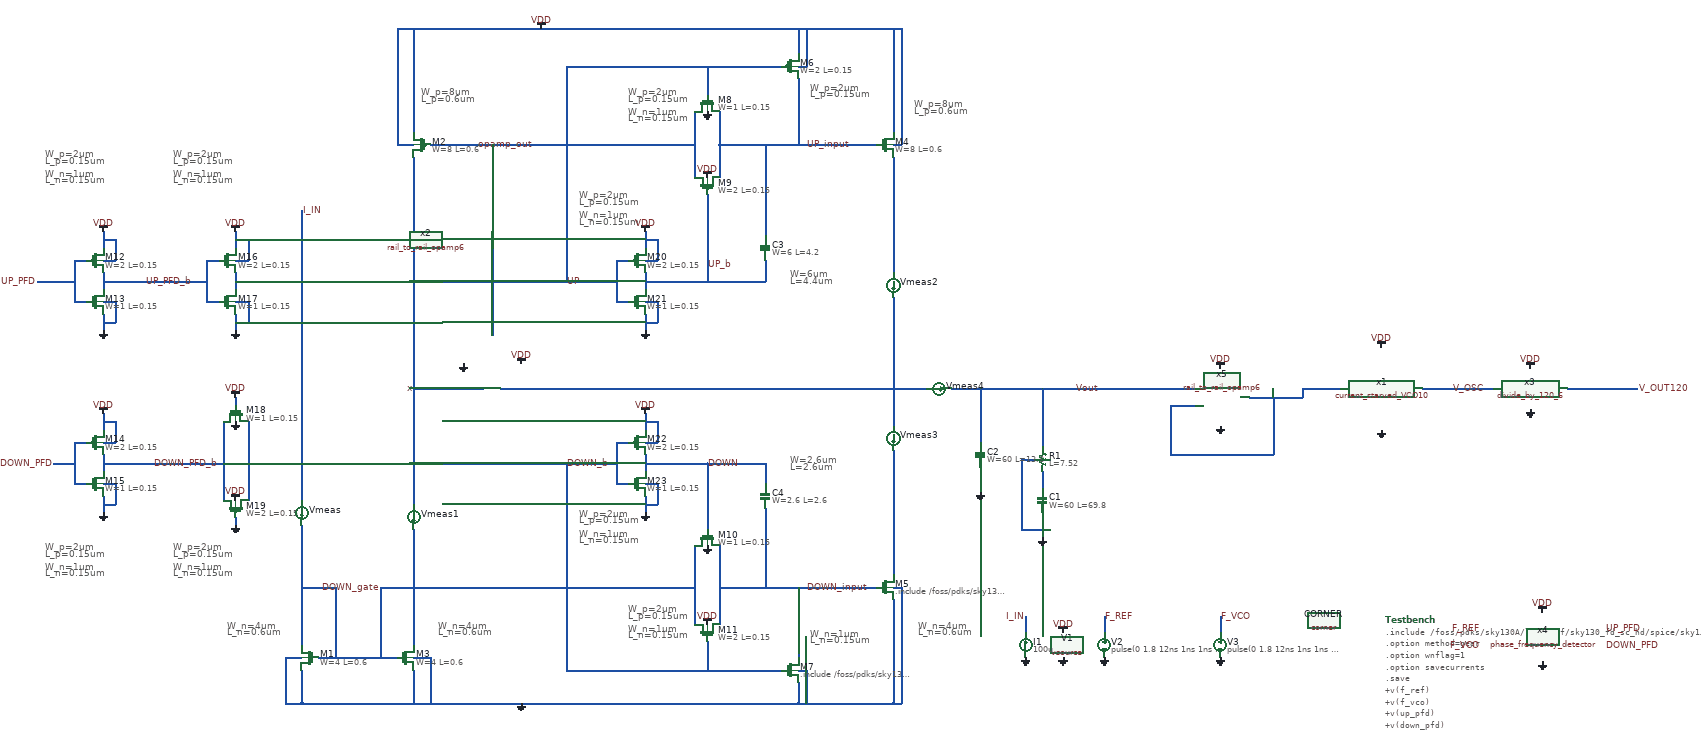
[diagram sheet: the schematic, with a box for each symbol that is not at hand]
v {xschem version=3.4.6 file_version=1.2}
G {}
K {}
V {}
S {}
E {}
B 2 2860 -2340 4220 -1670 {flags=graph
y1=0.88424229
y2=0.88833829
ypos1=0
ypos2=2
divy=5
subdivy=1
unity=1
x1=1.1050946e-07
x2=1.1771522e-07
divx=5
subdivx=1
xlabmag=1.0
ylabmag=1.0


dataset=0
unitx=1
logx=0
logy=0








linewidth_mult=1





color=6
node=vout}
B 2 2860 -3040 4220 -2370 {flags=graph
y1=-0.036
y2=1.7
ypos1=0
ypos2=2
divy=5
subdivy=1
unity=1
x1=1.1050946e-07
x2=1.1771522e-07
divx=5
subdivx=1
xlabmag=1.0
ylabmag=1.0


dataset=0
unitx=1
logx=0
logy=0








linewidth_mult=1




color=7
node=v_osc}
T {W_p=2um
L_p=0.15um

W_n=1um
L_n=0.15um} 550 -2010 0 0 0.4 0.4 {}
T {W_p=2um
L_p=0.15um

W_n=1um
L_n=0.15um} 550 -1060 0 0 0.4 0.4 {}
T {W_p=2um
L_p=0.15um

W_n=1um
L_n=0.15um} 860 -2010 0 0 0.4 0.4 {}
T {W_p=2um
L_p=0.15um

W_n=1um
L_n=0.15um} 860 -1060 0 0 0.4 0.4 {}
T {W_p=2um
L_p=0.15um

W_n=1um
L_n=0.15um} 1840 -1910 0 0 0.4 0.4 {}
T {W_p=2um
L_p=0.15um

W_n=1um
L_n=0.15um} 1840 -1140 0 0 0.4 0.4 {}
T {W_n=4um
L_n=0.6um} 990 -870 0 0 0.4 0.4 {}
T {W_n=4um
L_n=0.6um} 1500 -870 0 0 0.4 0.4 {}
T {W_p=2um
L_p=0.15um

W_n=1um
L_n=0.15um} 1960 -910 0 0 0.4 0.4 {}
T {W_p=2um
L_p=0.15um

W_n=1um
L_n=0.15um} 1960 -2160 0 0 0.4 0.4 {}
T {W_p=8um
L_p=0.6um} 1460 -2160 0 0 0.4 0.4 {}
T {W_p=8um
L_p=0.6um} 2650 -2130 0 0 0.4 0.4 {}
T {W_n=4um
L_n=0.6um} 2660 -870 0 0 0.4 0.4 {}
T {W_n=1um
L_n=0.15um} 2400 -850 0 0 0.4 0.4 {}
T {W_p=2um
L_p=0.15um} 2400 -2170 0 0 0.4 0.4 {}
T {W=2.6um
L=2.6um} 2350 -1270 0 0 0.4 0.4 {}
T {W=6um
L=4.4um} 2350 -1720 0 0 0.4 0.4 {}
N 2960 -1230 2960 -1180 {
lab=#net1}
N 2960 -1430 2960 -1290 {
lab=Vout}
N 2960 -1130 2960 -1070 {
lab=GND}
N 2910 -1260 2940 -1260 {
lab=GND}
N 2910 -1260 2910 -1090 {
lab=GND}
N 2910 -1090 2960 -1090 {
lab=GND}
N 2810 -1430 2810 -1290 {
lab=Vout}
N 2810 -1240 2810 -1180 {
lab=GND}
N 3110 -880 3110 -840 {
lab=F_REF}
N 3390 -880 3390 -840 {
lab=F_VCO}
N 2740 -1430 3040 -1430 {
lab=Vout}
N 2920 -880 2920 -840 {
lab=I_IN}
N 1210 -780 1400 -780 {
lab=DOWN_gate}
N 1170 -750 1170 -670 {
lab=GND}
N 1170 -670 1730 -670 {
lab=GND}
N 1130 -780 1170 -780 {
lab=GND}
N 1130 -780 1130 -670 {
lab=GND}
N 1130 -670 1170 -670 {
lab=GND}
N 1440 -780 1480 -780 {
lab=GND}
N 1400 -2020 1440 -2020 {
lab=VDD}
N 1730 -670 1770 -670 {
lab=GND}
N 1440 -2300 1440 -2050 {
lab=VDD}
N 1400 -2300 1400 -2020 {
lab=VDD}
N 2600 -2300 2600 -2050 {
lab=VDD}
N 2370 -2300 2370 -2240 {
lab=VDD}
N 2370 -2210 2390 -2210 {
lab=VDD}
N 2390 -2300 2390 -2210 {
lab=VDD}
N 2620 -2300 2620 -2020 {
lab=VDD}
N 2600 -2020 2620 -2020 {
lab=VDD}
N 2600 -1990 2600 -1710 {
lab=#net2}
N 1770 -670 2370 -670 {
lab=GND}
N 2370 -720 2370 -670 {
lab=GND}
N 2600 -950 2620 -950 {
lab=GND}
N 2600 -670 2620 -670 {
lab=GND}
N 790 -1690 890 -1690 {
lab=UP_PFD_b}
N 830 -1250 980 -1250 {
lab=DOWN_PFD_b}
N 530 -1690 570 -1690 {
lab=UP_PFD}
N 570 -1250 610 -1250 {
lab=DOWN_PFD}
N 1440 -1990 1440 -1550 {
lab=x}
N 1440 -1430 1610 -1430 {
lab=x}
N 1650 -1430 2600 -1430 {
lab=#net3}
N 1630 -2020 1630 -1560 {
lab=opamp_out}
N 1250 -950 1250 -780 {
lab=DOWN_gate}
N 1170 -950 1250 -950 {
lab=DOWN_gate}
N 1480 -780 1480 -670 {
lab=GND}
N 1440 -750 1440 -670 {
lab=GND}
N 1360 -950 2120 -950 {
lab=DOWN_gate}
N 1040 -1250 1880 -1250 {
lab=DOWN_b}
N 2150 -1900 2150 -1690 {
lab=UP_b}
N 1810 -2210 2330 -2210 {
lab=UP}
N 1810 -2210 1810 -1690 {
lab=UP}
N 2370 -2180 2370 -2020 {
lab=UP_input}
N 2180 -2020 2560 -2020 {
lab=UP_input}
N 1400 -2300 2620 -2300 {
lab=VDD}
N 2090 -1250 2150 -1250 {
lab=DOWN}
N 2150 -1250 2150 -1090 {
lab=DOWN}
N 1810 -1250 1810 -750 {
lab=DOWN_b}
N 1810 -750 2330 -750 {
lab=DOWN_b}
N 980 -1350 980 -1160 {
lab=DOWN_PFD_b}
N 1040 -1350 1040 -1160 {
lab=DOWN_b}
N 1010 -1410 1010 -1390 {
lab=VDD}
N 1010 -1120 1010 -1100 {
lab=GND}
N 690 -1270 690 -1230 {
lab=DOWN_PFD_b}
N 620 -1300 650 -1300 {
lab=DOWN_PFD}
N 620 -1300 620 -1200 {
lab=DOWN_PFD}
N 620 -1200 650 -1200 {
lab=DOWN_PFD}
N 690 -1250 830 -1250 {
lab=DOWN_PFD_b}
N 610 -1250 620 -1250 {
lab=DOWN_PFD}
N 690 -1170 690 -1130 {
lab=GND}
N 690 -1370 690 -1330 {
lab=VDD}
N 690 -1300 720 -1300 {
lab=VDD}
N 720 -1350 720 -1300 {
lab=VDD}
N 690 -1350 720 -1350 {
lab=VDD}
N 690 -1200 720 -1200 {
lab=GND}
N 720 -1200 720 -1150 {
lab=GND}
N 690 -1150 720 -1150 {
lab=GND}
N 690 -1710 690 -1670 {
lab=UP_PFD_b}
N 620 -1740 650 -1740 {
lab=UP_PFD}
N 620 -1740 620 -1640 {
lab=UP_PFD}
N 620 -1640 650 -1640 {
lab=UP_PFD}
N 690 -1690 790 -1690 {
lab=UP_PFD_b}
N 570 -1690 620 -1690 {
lab=UP_PFD}
N 690 -1610 690 -1570 {
lab=GND}
N 690 -1810 690 -1770 {
lab=VDD}
N 690 -1740 720 -1740 {
lab=VDD}
N 720 -1790 720 -1740 {
lab=VDD}
N 690 -1790 720 -1790 {
lab=VDD}
N 690 -1640 720 -1640 {
lab=GND}
N 720 -1640 720 -1590 {
lab=GND}
N 690 -1590 720 -1590 {
lab=GND}
N 1010 -1710 1010 -1670 {
lab=UP}
N 940 -1740 970 -1740 {
lab=UP_PFD_b}
N 940 -1740 940 -1640 {
lab=UP_PFD_b}
N 940 -1640 970 -1640 {
lab=UP_PFD_b}
N 890 -1690 940 -1690 {
lab=UP_PFD_b}
N 1010 -1610 1010 -1570 {
lab=GND}
N 1010 -1810 1010 -1770 {
lab=VDD}
N 1010 -1740 1040 -1740 {
lab=VDD}
N 1040 -1790 1040 -1740 {
lab=VDD}
N 1010 -1790 1040 -1790 {
lab=VDD}
N 1010 -1640 1040 -1640 {
lab=GND}
N 1040 -1640 1040 -1590 {
lab=GND}
N 1010 -1590 1040 -1590 {
lab=GND}
N 2000 -1270 2000 -1230 {
lab=DOWN}
N 1930 -1300 1960 -1300 {
lab=DOWN_b}
N 1930 -1300 1930 -1200 {
lab=DOWN_b}
N 1930 -1200 1960 -1200 {
lab=DOWN_b}
N 1880 -1250 1930 -1250 {
lab=DOWN_b}
N 2000 -1170 2000 -1130 {
lab=GND}
N 2000 -1370 2000 -1330 {
lab=VDD}
N 2000 -1300 2030 -1300 {
lab=VDD}
N 2030 -1350 2030 -1300 {
lab=VDD}
N 2000 -1350 2030 -1350 {
lab=VDD}
N 2000 -1200 2030 -1200 {
lab=GND}
N 2030 -1200 2030 -1150 {
lab=GND}
N 2000 -1150 2030 -1150 {
lab=GND}
N 2000 -1250 2090 -1250 {
lab=DOWN}
N 2000 -1710 2000 -1670 {
lab=UP_b}
N 1930 -1740 1960 -1740 {
lab=UP}
N 1930 -1740 1930 -1640 {
lab=UP}
N 1930 -1640 1960 -1640 {
lab=UP}
N 1810 -1690 1930 -1690 {
lab=UP}
N 2000 -1610 2000 -1570 {
lab=GND}
N 2000 -1810 2000 -1770 {
lab=VDD}
N 2000 -1740 2030 -1740 {
lab=VDD}
N 2030 -1790 2030 -1740 {
lab=VDD}
N 2000 -1790 2030 -1790 {
lab=VDD}
N 2000 -1640 2030 -1640 {
lab=GND}
N 2030 -1640 2030 -1590 {
lab=GND}
N 2000 -1590 2030 -1590 {
lab=GND}
N 2000 -1690 2090 -1690 {
lab=UP_b}
N 2090 -1690 2150 -1690 {
lab=UP_b}
N 1010 -1690 1810 -1690 {
lab=UP}
N 1440 -1550 1440 -1490 {
lab=x}
N 1170 -1860 1170 -1160 {
lab=I_IN}
N 1440 -1490 1440 -1150 {
lab=x}
N 1440 -1070 1440 -810 {
lab=#net4}
N 1170 -1100 1170 -1090 {
lab=DOWN_gate}
N 1170 -990 1170 -810 {
lab=DOWN_gate}
N 1440 -1090 1440 -1070 {
lab=#net4}
N 1170 -1090 1170 -990 {
lab=DOWN_gate}
N 2180 -2100 2180 -2020 {
lab=UP_input}
N 2120 -2100 2120 -1940 {
lab=opamp_out}
N 2180 -2020 2180 -1940 {
lab=UP_input}
N 1480 -2020 2120 -2020 {
lab=opamp_out}
N 2370 -670 2600 -670 {
lab=GND}
N 2180 -1050 2180 -860 {
lab=DOWN_input}
N 2120 -1050 2120 -860 {
lab=DOWN_gate}
N 2180 -950 2560 -950 {
lab=DOWN_input}
N 2600 -920 2600 -670 {
lab=GND}
N 2620 -950 2620 -670 {
lab=GND}
N 1360 -950 1360 -780 {
lab=DOWN_gate}
N 2370 -950 2370 -780 {
lab=DOWN_input}
N 2370 -750 2390 -750 {
lab=GND}
N 2390 -750 2390 -670 {
lab=GND}
N 2150 -2210 2150 -2140 {
lab=UP}
N 2600 -1280 2600 -980 {
lab=#net5}
N 2600 -1430 2600 -1340 {
lab=#net3}
N 2600 -1650 2600 -1430 {
lab=#net3}
N 2150 -1690 2290 -1690 {
lab=UP_b}
N 2290 -1740 2290 -1690 {
lab=UP_b}
N 2290 -2020 2290 -1800 {
lab=UP_input}
N 2290 -1250 2290 -1200 {
lab=DOWN}
N 2290 -1140 2290 -950 {
lab=DOWN_input}
N 2150 -1250 2290 -1250 {
lab=DOWN}
N 2600 -1430 2680 -1430 {
lab=#net3}
N 2150 -820 2150 -750 {
lab=DOWN_b}
N 3880 -1430 4050 -1430 {lab=V_OSC}
N 4230 -1430 4400 -1430 {lab=V_OUT120}
N 3040 -1430 3260 -1430 {lab=Vout}
N 3260 -1430 3330 -1430 {lab=Vout}
N 3460 -1410 3590 -1410 {lab=#net6}
N 3590 -1430 3590 -1410 {lab=#net6}
N 3590 -1430 3680 -1430 {lab=#net6}
N 3520 -1410 3520 -1270 {lab=#net6}
N 3270 -1270 3520 -1270 {lab=#net6}
N 3270 -1390 3270 -1270 {lab=#net6}
N 3270 -1390 3330 -1390 {lab=#net6}
C {sky130_fd_pr/corner.sym} 3640 -870 0 0 {name=CORNER only_toplevel=false corner=tt
value="

.include /foss/pdks/sky130A/libs.ref/sky130_fd_sc_hd/spice/sky130_fd_sc_hd.spice

.option method=gear
.option wnflag=1

* V_out initial voltage value for the F_VCO delay of 2ns  (leading)
* .ic v(vout) = 1.8

* V_out initial voltage value for the F_VCO delay of 12ns (lock condition)
.ic v(vout) = 0.83

* V_out initial voltage value for the F_VCO delay of 22ns (lagging)
* .ic v(vout) = 0

.control
  save v(f_ref) save v(f_vco) save v(i_in) save v(up_pfd) v(down_pfd) v(up_pfd_b) v(down_pfd_b) v(up) v(up_b) v(down) v(down_b) v(x) v(opamp_out) v(up_input) v(down_input) v(down_gate) v(vout)

  * timestep for exact simulation results
  * tran 5ps 0.5us

  * timestep for faster simulation results
  tran 50ps 0.5us

  remzerovec
  write pfd_charge_pump_10.raw
  set appendwrite

.endc

"


v(vout)="0.0

.control
  save all

  * timestep for exact simulation results
  tran 5ps 0.5us

  * timestep for faster simulation results
  * tran 50ps 0.5us

  remzerovec
  write pfd_chargA}
C {devices/code.sym} 3790 -871.25 0 0 {name=Testbench only_toplevel=false value="

.include /foss/pdks/sky130A/libs.ref/sky130_fd_sc_hd/spice/sky130_fd_sc_hd.spice

.option method=gear
.option wnflag=1
.option savecurrents

.save
+v(f_ref)
+v(f_vco)
+v(up_pfd)
+v(down_pfd)
+v(x4.up_pfd_b)
+v(x4.up_b)
+v(x4.down_b)
+v(x4.up)
+v(x4.down)
+v(x4.up_input)
+v(x4.down_input)
+v(x4.down_gate)
+v(x4.x)
+v(x4.opamp_out)
+i(x4.vmeas2)
+i(x4.vmeas3)
+@m.x2.xm1.msky130_fd_pr__nfet_01v8[gm]
+@m.x2.xm2.msky130_fd_pr__nfet_01v8[gm]
+@m.x2.xm3.msky130_fd_pr__nfet_01v8[gm]
+@m.x2.xm4.msky130_fd_pr__pfet_01v8[gm]
+@m.x2.xm5.msky130_fd_pr__pfet_01v8[gm]
+@m.x2.xm6.msky130_fd_pr__pfet_01v8[gm]
+@m.x2.xm7.msky130_fd_pr__pfet_01v8[gm]
+@m.x2.xm8.msky130_fd_pr__pfet_01v8[gm]
+@m.x2.xm9.msky130_fd_pr__nfet_01v8[gm]
+@m.x2.xm10.msky130_fd_pr__nfet_01v8[gm]
+@m.x2.xm11.msky130_fd_pr__pfet_01v8[gm]
+@m.x2.xm12.msky130_fd_pr__nfet_01v8[gm]
+@m.x2.xm13.msky130_fd_pr__pfet_01v8[gm]
+@m.x2.xm15.msky130_fd_pr__nfet_01v8[gm]
+v(v_cont)
+v(v_osc)
+v(vout)
+v(v_out120)

* V_out initial voltage value for the F_VCO delay of 2ns  (leading)
* .ic v(vout) = 1.8

* V_out initial voltage value for the F_VCO delay of 12ns (lock condition)
.ic v(vout) = 0.887

* V_out initial voltage value for the F_VCO delay of 22ns (lagging)
* .ic v(vout) = 0.0

.control
  * save v(f_ref) save v(f_vco) save v(i_in) save v(up_pfd) v(down_pfd) v(up_pfd_b) v(down_pfd_b) v(up) v(up_b) v(down) v(down_b) v(x) v(opamp_out) v(up_input) v(down_input) v(down_gate) v(vout)
  * save all

  * timestep for exact simulation results
  tran 5ps 0.5us

  * timestep for faster simulation results
  * tran 50ps 0.5us

  remzerovec
  write pfd_charge_pump_14.raw
  set appendwrite

.endc

"
}
C {devices/vsource.sym} 3010 -810 0 0 {name=V1 value=1.8 savecurrent=false}
C {devices/gnd.sym} 3010 -780 0 0 {name=l2 lab=GND}
C {devices/vdd.sym} 3010 -840 0 1 {name=l3 lab=VDD}
C {devices/lab_wire.sym} 3040 -1430 0 1 {name=p9 sig_type=std_logic lab=Vout}
C {sky130_fd_pr/cap_mim_m3_1.sym} 2810 -1270 0 0 {name=C2 model=cap_mim_m3_1 W=60 L=13.8 MF=1 spiceprefix=X}
C {sky130_fd_pr/cap_mim_m3_1.sym} 2960 -1160 0 0 {name=C1 model=cap_mim_m3_1 W=60 L=69.8 MF=1 spiceprefix=X}
C {devices/gnd.sym} 2960 -1070 0 0 {name=l4 lab=GND
value="

.include /foss/pdks/sky130A/libs.ref/sky130_fd_sc_hd/spice/sky130_fd_sc_hd.spice

.option method=gear
.option wnflag=1

* V_out initial voltage value for the F_VCO delay of 2ns  (leading)
* .ic v(vout) = 1.8

* V_out initial voltage value for the F_VCO delay of 12ns (lock condition)
.ic v(vout) = 0.83

* V_out initial voltage value for the F_VCO delay of 22ns (lagging)
* .ic v(vout) = 0

.control
  save v(f_ref) save v(f_vco) save v(i_in) save v(up_pfd) v(down_pfd) v(up_pfd_b) v(down_pfd_b) v(up) v(up_b) v(down) v(down_b) v(x) v(opamp_out) v(up_input) v(down_input) v(down_gate) v(vout)

  * timestep for exact simulation results
  * tran 5ps 0.5us

  * timestep for faster simulation results
  tran 50ps 0.5us

  remzerovec
  write pfd_charge_pump_10.raw
  set appendwrite

.endc

"}
C {devices/gnd.sym} 2810 -1180 0 0 {name=l9 lab=GND
W=60}
C {devices/vsource.sym} 3110 -810 0 0 {name=V2 value=pulse"(0 1.8 12ns 1ns 1ns 24ns 50ns)" savecurrent=false
* }
C {devices/gnd.sym} 3110 -780 0 0 {name=l10 lab=GND}
C {devices/lab_pin.sym} 3110 -880 0 1 {name=p11 sig_type=std_logic lab=F_REF}
C {devices/vsource.sym} 3390 -810 0 0 {name=V3 value="pulse(0 1.8 12ns 1ns 1ns 24ns 50ns)" savecurrent=false
* "sin(0.9 0.9 20.1MEG)" 1 AC 1}
C {devices/gnd.sym} 3390 -780 0 0 {name=l15 lab=GND}
C {devices/lab_pin.sym} 3390 -880 0 1 {name=p12 sig_type=std_logic lab=F_VCO}
C {/foss/designs/my_design/projects/pll/pfd/xschem_ngspice/phase_frequency_detector.sym} 4170 -830 0 0 {name=x4
value="

.include /foss/pdks/sky130A/libs.ref/sky130_fd_sc_hd/spice/sky130_fd_sc_hd.spice

.option method=gear
.option wnflag=1

* V_out initial voltage value for the F_VCO delay of 2ns  (leading)
* .ic v(vout) = 1.8

* V_out initial voltage value for the F_VCO delay of 12ns (lock condition)
.ic v(vout) = 0.83

* V_out initial voltage value for the F_VCO delay of 22ns (lagging)
* .ic v(vout) = 0

.control
  save v(f_ref) save v(f_vco) save v(i_in) save v(up_pfd) v(down_pfd) v(up_pfd_b) v(down_pfd_b) v(up) v(up_b) v(down) v(down_b) v(x) v(opamp_out) v(up_input) v(down_input) v(down_gate) v(vout)

  * timestep for exact simulation results
  * tran 5ps 0.5us

  * timestep for faster simulation results
  tran 50ps 0.5us

  remzerovec
  write pfd_charge_pump_10.raw
  set appendwrite

.endc

"


v(vout)="0.0

.control
  save all

  * timestep for exact simulation results
  tran 5ps 0.5us

  * timestep for faster simulation results
  * tran 50ps 0.5us

  remzerovec
  write pfd_charge_pump_10.raw
  set appendwrite

.!}
C {devices/lab_pin.sym} 4020 -850 0 0 {name=p19 lab=F_REF
value="

.include /foss/pdks/sky130A/libs.ref/sky130_fd_sc_hd/spice/sky130_fd_sc_hd.spice

.option method=gear
.option wnflag=1

* V_out initial voltage value for the F_VCO delay of 2ns  (leading)
* .ic v(vout) = 1.8

* V_out initial voltage value for the F_VCO delay of 12ns (lock condition)
.ic v(vout) = 0.83

* V_out initial voltage value for the F_VCO delay of 22ns (lagging)
* .ic v(vout) = 0

.control
  save v(f_ref) save v(f_vco) save v(i_in) save v(up_pfd) v(down_pfd) v(up_pfd_b) v(down_pfd_b) v(up) v(up_b) v(down) v(down_b) v(x) v(opamp_out) v(up_input) v(down_input) v(down_gate) v(vout)

  * timestep for exact simulation results
  * tran 5ps 0.5us

  * timestep for faster simulation results
  tran 50ps 0.5us

  remzerovec
  write pfd_charge_pump_10.raw
  set appendwrite

.endc

"


v(vout)="0.0

.control
  save all

  * timestep for exact simulation results
  tran 5ps 0.5us

  * timestep for faster simulation results
  * tran 50ps 0.5us

  remzerovec
  write pfd_charge_pump_10.raw
  set appA}
C {devices/lab_pin.sym} 4020 -810 0 0 {name=p20 lab=F_VCO
value="

.include /foss/pdks/sky130A/libs.ref/sky130_fd_sc_hd/spice/sky130_fd_sc_hd.spice

.option method=gear
.option wnflag=1

* V_out initial voltage value for the F_VCO delay of 2ns  (leading)
* .ic v(vout) = 1.8

* V_out initial voltage value for the F_VCO delay of 12ns (lock condition)
.ic v(vout) = 0.83

* V_out initial voltage value for the F_VCO delay of 22ns (lagging)
* .ic v(vout) = 0

.control
  save v(f_ref) save v(f_vco) save v(i_in) save v(up_pfd) v(down_pfd) v(up_pfd_b) v(down_pfd_b) v(up) v(up_b) v(down) v(down_b) v(x) v(opamp_out) v(up_input) v(down_input) v(down_gate) v(vout)

  * timestep for exact simulation results
  * tran 5ps 0.5us

  * timestep for faster simulation results
  tran 50ps 0.5us

  remzerovec
  write pfd_charge_pump_10.raw
  set appendwrite

.endc

"


v(vout)="0.0

.control
  save all

  * timestep for exact simulation results
  tran 5ps 0.5us

  * timestep for faster simulation results
  * tran 50ps 0.5us

  remzerovec
  write pfd_charge_pump_10.raw
  set appA}
C {devices/lab_wire.sym} 4320 -850 0 1 {name=p22 sig_type=std_logic lab=UP_PFD}
C {devices/lab_wire.sym} 4320 -810 2 0 {name=p23 sig_type=std_logic lab=DOWN_PFD}
C {devices/vdd.sym} 4170 -890 0 1 {name=l1 lab=VDD
value="

.include /foss/pdks/sky130A/libs.ref/sky130_fd_sc_hd/spice/sky130_fd_sc_hd.spice

.option method=gear
.option wnflag=1

* V_out initial voltage value for the F_VCO delay of 2ns  (leading)
* .ic v(vout) = 1.8

* V_out initial voltage value for the F_VCO delay of 12ns (lock condition)
.ic v(vout) = 0.83

* V_out initial voltage value for the F_VCO delay of 22ns (lagging)
* .ic v(vout) = 0

.control
  save v(f_ref) save v(f_vco) save v(i_in) save v(up_pfd) v(down_pfd) v(up_pfd_b) v(down_pfd_b) v(up) v(up_b) v(down) v(down_b) v(x) v(opamp_out) v(up_input) v(down_input) v(down_gate) v(vout)

  * timestep for exact simulation results
  * tran 5ps 0.5us

  * timestep for faster simulation results
  tran 50ps 0.5us

  remzerovec
  write pfd_charge_pump_10.raw
  set appendwrite

.endc

"


v(vout)="0.0

.control
  save all

  * timestep for exact simulation results
  tran 5ps 0.5us

  * timestep for faster simulation results
  * tran 50ps 0.5us

  remzerovec
  write pfd_charge_pump_10.raw
  set appendA}
C {devices/gnd.sym} 4170 -770 0 0 {name=l8 lab=GND
value="

.include /foss/pdks/sky130A/libs.ref/sky130_fd_sc_hd/spice/sky130_fd_sc_hd.spice

.option method=gear
.option wnflag=1

* V_out initial voltage value for the F_VCO delay of 2ns  (leading)
* .ic v(vout) = 1.8

* V_out initial voltage value for the F_VCO delay of 12ns (lock condition)
.ic v(vout) = 0.83

* V_out initial voltage value for the F_VCO delay of 22ns (lagging)
* .ic v(vout) = 0

.control
  save v(f_ref) save v(f_vco) save v(i_in) save v(up_pfd) v(down_pfd) v(up_pfd_b) v(down_pfd_b) v(up) v(up_b) v(down) v(down_b) v(x) v(opamp_out) v(up_input) v(down_input) v(down_gate) v(vout)

  * timestep for exact simulation results
  * tran 5ps 0.5us

  * timestep for faster simulation results
  tran 50ps 0.5us

  remzerovec
  write pfd_charge_pump_10.raw
  set appendwrite

.endc

"}
C {sky130_fd_pr/res_xhigh_po_0p35.sym} 2960 -1260 0 0 {name=R1
L=7.52
model=res_xhigh_po_0p35
spiceprefix=X
mult=1}
C {devices/isource.sym} 2920 -810 2 0 {name=I1 value=100u}
C {devices/gnd.sym} 2920 -780 0 0 {name=l26 lab=GND}
C {devices/lab_pin.sym} 2920 -880 2 1 {name=p3 sig_type=std_logic lab=I_IN}
C {devices/ammeter.sym} 2600 -1310 0 0 {name=Vmeas3 savecurrent=true spice_ignore=0}
C {sky130_fd_pr/nfet_01v8.sym} 1190 -780 0 1 {name=M1
L=0.6
W=4
nf=1 
mult=1
ad="'int((nf+1)/2) * W/nf * 0.29'" 
pd="'2*int((nf+1)/2) * (W/nf + 0.29)'"
as="'int((nf+2)/2) * W/nf * 0.29'" 
ps="'2*int((nf+2)/2) * (W/nf + 0.29)'"
nrd="'0.29 / W'" nrs="'0.29 / W'"
sa=0 sb=0 sd=0
model=nfet_01v8
spiceprefix=X
}
C {sky130_fd_pr/nfet_01v8.sym} 1420 -780 0 0 {name=M3
L=0.6
W=4
nf=1 
mult=1
ad="'int((nf+1)/2) * W/nf * 0.29'" 
pd="'2*int((nf+1)/2) * (W/nf + 0.29)'"
as="'int((nf+2)/2) * W/nf * 0.29'" 
ps="'2*int((nf+2)/2) * (W/nf + 0.29)'"
nrd="'0.29 / W'" nrs="'0.29 / W'"
sa=0 sb=0 sd=0
model=nfet_01v8
spiceprefix=X
}
C {sky130_fd_pr/pfet_01v8.sym} 1460 -2020 2 0 {name=M2
L=0.6
W=8
nf=8
mult=1
ad="'int((nf+1)/2) * W/nf * 0.29'" 
pd="'2*int((nf+1)/2) * (W/nf + 0.29)'"
as="'int((nf+2)/2) * W/nf * 0.29'" 
ps="'2*int((nf+2)/2) * (W/nf + 0.29)'"
nrd="'0.29 / W'" nrs="'0.29 / W'"
sa=0 sb=0 sd=0
model=pfet_01v8
spiceprefix=X
}
C {devices/vdd.sym} 1750 -2300 0 0 {name=l13 lab=VDD}
C {devices/gnd.sym} 1700 -670 0 0 {name=l14 lab=GND}
C {devices/lab_wire.sym} 1440 -1430 0 0 {name=p2 sig_type=std_logic lab=x}
C {sky130_fd_pr/pfet_01v8.sym} 2150 -1920 1 1 {name=M9
L=0.15
W=2
nf=2
mult=1
ad="'int((nf+1)/2) * W/nf * 0.29'" 
pd="'2*int((nf+1)/2) * (W/nf + 0.29)'"
as="'int((nf+2)/2) * W/nf * 0.29'" 
ps="'2*int((nf+2)/2) * (W/nf + 0.29)'"
nrd="'0.29 / W'" nrs="'0.29 / W'"
sa=0 sb=0 sd=0
model=pfet_01v8
spiceprefix=X
}
C {sky130_fd_pr/pfet_01v8.sym} 2350 -2210 0 0 {name=M6
L=0.15
W=2
nf=2
mult=1
ad="'int((nf+1)/2) * W/nf * 0.29'" 
pd="'2*int((nf+1)/2) * (W/nf + 0.29)'"
as="'int((nf+2)/2) * W/nf * 0.29'" 
ps="'2*int((nf+2)/2) * (W/nf + 0.29)'"
nrd="'0.29 / W'" nrs="'0.29 / W'"
sa=0 sb=0 sd=0
model=pfet_01v8
spiceprefix=X
}
C {sky130_fd_pr/pfet_01v8.sym} 2580 -2020 0 0 {name=M4
L=0.6
W=8
nf=8
mult=1
ad="'int((nf+1)/2) * W/nf * 0.29'" 
pd="'2*int((nf+1)/2) * (W/nf + 0.29)'"
as="'int((nf+2)/2) * W/nf * 0.29'" 
ps="'2*int((nf+2)/2) * (W/nf + 0.29)'"
nrd="'0.29 / W'" nrs="'0.29 / W'"
sa=0 sb=0 sd=0
model=pfet_01v8
spiceprefix=X
}
C {devices/lab_wire.sym} 1810 -1690 2 0 {name=p4 sig_type=std_logic lab=UP}
C {devices/lab_wire.sym} 2150 -1730 0 1 {name=p5 sig_type=std_logic lab=UP_b}
C {sky130_fd_pr/nfet_01v8.sym} 2150 -1070 1 0 {name=M10
L=0.15
W=1
nf=1 
mult=1
ad="'int((nf+1)/2) * W/nf * 0.29'" 
pd="'2*int((nf+1)/2) * (W/nf + 0.29)'"
as="'int((nf+2)/2) * W/nf * 0.29'" 
ps="'2*int((nf+2)/2) * (W/nf + 0.29)'"
nrd="'0.29 / W'" nrs="'0.29 / W'"
sa=0 sb=0 sd=0
model=nfet_01v8
spiceprefix=X
}
C {sky130_fd_pr/nfet_01v8.sym} 2350 -750 0 0 {name=M7
L=0.15
W=1
nf=1 
mult=1
ad="'int((nf+1)/2) * W/nf * 0.29'" 
pd="'2*int((nf+1)/2) * (W/nf + 0.29)'"
as="'int((nf+2)/2) * W/nf * 0.29'" 
ps="'2*int((nf+2)/2) * (W/nf + 0.29)'"
nrd="'0.29 / W'" nrs="'0.29 / W'"
sa=0 sb=0 sd=0
model=nfet_01v8
spiceprefix=X
value="

.include /foss/pdks/sky130A/libs.ref/sky130_fd_sc_hd/spice/sky130_fd_sc_hd.spice

.option method=gear
.option wnflag=1

* V_out initial voltage value for the F_VCO delay of 2ns  (leading)
* .ic v(vout) = 1.8

* V_out initial voltage value for the F_VCO delay of 12ns (lock condition)
.ic v(vout) = 0.83

* V_out initial voltage value for the F_VCO delay of 22ns (lagging)
* .ic v(vout) = 0

.control
  save v(f_ref) save v(f_vco) save v(i_in) save v(up_pfd) v(down_pfd) v(up_pfd_b) v(down_pfd_b) v(up) v(up_b) v(down) v(down_b) v(x) v(opamp_out) v(up_input) v(down_input) v(down_gate) v(vout)

  * timestep for exact simulation results
  * tran 5ps 0.5us

  * timestep for faster simulation results
  tran 50ps 0.5us

  remzerovec
  write pfd_charge_pump_10.raw
  set appendwrite

.endc

"}
C {devices/lab_wire.sym} 1810 -1250 0 1 {name=p6 sig_type=std_logic lab=DOWN_b}
C {sky130_fd_pr/nfet_01v8.sym} 2580 -950 0 0 {name=M5
L=0.6
W=4
nf=1 
mult=1
ad="'int((nf+1)/2) * W/nf * 0.29'" 
pd="'2*int((nf+1)/2) * (W/nf + 0.29)'"
as="'int((nf+2)/2) * W/nf * 0.29'" 
ps="'2*int((nf+2)/2) * (W/nf + 0.29)'"
nrd="'0.29 / W'" nrs="'0.29 / W'"
sa=0 sb=0 sd=0
model=nfet_01v8
spiceprefix=X
value="

.include /foss/pdks/sky130A/libs.ref/sky130_fd_sc_hd/spice/sky130_fd_sc_hd.spice

.option method=gear
.option wnflag=1

* V_out initial voltage value for the F_VCO delay of 2ns  (leading)
* .ic v(vout) = 1.8

* V_out initial voltage value for the F_VCO delay of 12ns (lock condition)
.ic v(vout) = 0.83

* V_out initial voltage value for the F_VCO delay of 22ns (lagging)
* .ic v(vout) = 0

.control
  save v(f_ref) save v(f_vco) save v(i_in) save v(up_pfd) v(down_pfd) v(up_pfd_b) v(down_pfd_b) v(up) v(up_b) v(down) v(down_b) v(x) v(opamp_out) v(up_input) v(down_input) v(down_gate) v(vout)

  * timestep for exact simulation results
  * tran 5ps 0.5us

  * timestep for faster simulation results
  tran 50ps 0.5us

  remzerovec
  write pfd_charge_pump_10.raw
  set appendwrite

.endc

"}
C {devices/lab_wire.sym} 790 -1690 0 1 {name=p15 sig_type=std_logic lab=UP_PFD_b}
C {devices/lab_wire.sym} 2390 -2020 2 0 {name=p13 sig_type=std_logic lab=UP_input}
C {devices/lab_wire.sym} 2390 -950 0 1 {name=p14 sig_type=std_logic lab=DOWN_input
value="

.include /foss/pdks/sky130A/libs.ref/sky130_fd_sc_hd/spice/sky130_fd_sc_hd.spice

.option method=gear
.option wnflag=1

* V_out initial voltage value for the F_VCO delay of 2ns  (leading)
* .ic v(vout) = 1.8

* V_out initial voltage value for the F_VCO delay of 12ns (lock condition)
.ic v(vout) = 0.83

* V_out initial voltage value for the F_VCO delay of 22ns (lagging)
* .ic v(vout) = 0

.control
  save v(f_ref) save v(f_vco) save v(i_in) save v(up_pfd) v(down_pfd) v(up_pfd_b) v(down_pfd_b) v(up) v(up_b) v(down) v(down_b) v(x) v(opamp_out) v(up_input) v(down_input) v(down_gate) v(vout)

  * timestep for exact simulation results
  * tran 5ps 0.5us

  * timestep for faster simulation results
  tran 50ps 0.5us

  remzerovec
  write pfd_charge_pump_10.raw
  set appendwrite

.endc

"}
C {devices/gnd.sym} 1560 -1490 0 1 {name=l7 lab=GND}
C {devices/lab_wire.sym} 1730 -2020 0 0 {name=p17 sig_type=std_logic lab=opamp_out}
C {devices/lab_wire.sym} 530 -1690 0 0 {name=p7 sig_type=std_logic lab=UP_PFD}
C {devices/lab_wire.sym} 570 -1250 2 1 {name=p8 sig_type=std_logic lab=DOWN_PFD}
C {/foss/designs/my_design/projects/pll/charge_pump/xschem_ngspice/rail_to_rail_opamp6.sym} 1630 -1490 1 1 {name=x2}
C {devices/vdd.sym} 1700 -1490 0 0 {name=l6 lab=VDD}
C {sky130_fd_pr/pfet_01v8.sym} 1010 -1140 3 0 {name=M19
L=0.15
W=2
nf=2
mult=1
ad="'int((nf+1)/2) * W/nf * 0.29'" 
pd="'2*int((nf+1)/2) * (W/nf + 0.29)'"
as="'int((nf+2)/2) * W/nf * 0.29'" 
ps="'2*int((nf+2)/2) * (W/nf + 0.29)'"
nrd="'0.29 / W'" nrs="'0.29 / W'"
sa=0 sb=0 sd=0
model=pfet_01v8
spiceprefix=X
}
C {sky130_fd_pr/nfet_01v8.sym} 1010 -1370 1 0 {name=M18
L=0.15
W=1
nf=1 
mult=1
ad="'int((nf+1)/2) * W/nf * 0.29'" 
pd="'2*int((nf+1)/2) * (W/nf + 0.29)'"
as="'int((nf+2)/2) * W/nf * 0.29'" 
ps="'2*int((nf+2)/2) * (W/nf + 0.29)'"
nrd="'0.29 / W'" nrs="'0.29 / W'"
sa=0 sb=0 sd=0
model=nfet_01v8
spiceprefix=X
}
C {devices/vdd.sym} 1010 -1410 0 0 {name=l11 lab=VDD}
C {devices/gnd.sym} 1010 -1100 0 0 {name=l12 lab=GND}
C {sky130_fd_pr/pfet_01v8.sym} 670 -1300 0 0 {name=M14
L=0.15
W=2
nf=2
mult=1
ad="'int((nf+1)/2) * W/nf * 0.29'" 
pd="'2*int((nf+1)/2) * (W/nf + 0.29)'"
as="'int((nf+2)/2) * W/nf * 0.29'" 
ps="'2*int((nf+2)/2) * (W/nf + 0.29)'"
nrd="'0.29 / W'" nrs="'0.29 / W'"
sa=0 sb=0 sd=0
model=pfet_01v8
spiceprefix=X
}
C {sky130_fd_pr/nfet_01v8.sym} 670 -1200 2 1 {name=M15
L=0.15
W=1
nf=1 
mult=1
ad="'int((nf+1)/2) * W/nf * 0.29'" 
pd="'2*int((nf+1)/2) * (W/nf + 0.29)'"
as="'int((nf+2)/2) * W/nf * 0.29'" 
ps="'2*int((nf+2)/2) * (W/nf + 0.29)'"
nrd="'0.29 / W'" nrs="'0.29 / W'"
sa=0 sb=0 sd=0
model=nfet_01v8
spiceprefix=X
}
C {devices/gnd.sym} 690 -1130 0 0 {name=l16 lab=GND}
C {devices/vdd.sym} 690 -1370 0 0 {name=l17 lab=VDD}
C {sky130_fd_pr/pfet_01v8.sym} 670 -1740 0 0 {name=M12
L=0.15
W=2
nf=2
mult=1
ad="'int((nf+1)/2) * W/nf * 0.29'" 
pd="'2*int((nf+1)/2) * (W/nf + 0.29)'"
as="'int((nf+2)/2) * W/nf * 0.29'" 
ps="'2*int((nf+2)/2) * (W/nf + 0.29)'"
nrd="'0.29 / W'" nrs="'0.29 / W'"
sa=0 sb=0 sd=0
model=pfet_01v8
spiceprefix=X
}
C {sky130_fd_pr/nfet_01v8.sym} 670 -1640 2 1 {name=M13
L=0.15
W=1
nf=1 
mult=1
ad="'int((nf+1)/2) * W/nf * 0.29'" 
pd="'2*int((nf+1)/2) * (W/nf + 0.29)'"
as="'int((nf+2)/2) * W/nf * 0.29'" 
ps="'2*int((nf+2)/2) * (W/nf + 0.29)'"
nrd="'0.29 / W'" nrs="'0.29 / W'"
sa=0 sb=0 sd=0
model=nfet_01v8
spiceprefix=X
}
C {devices/gnd.sym} 690 -1570 0 0 {name=l18 lab=GND}
C {devices/vdd.sym} 690 -1810 0 0 {name=l19 lab=VDD}
C {sky130_fd_pr/pfet_01v8.sym} 990 -1740 0 0 {name=M16
L=0.15
W=2
nf=2
mult=1
ad="'int((nf+1)/2) * W/nf * 0.29'" 
pd="'2*int((nf+1)/2) * (W/nf + 0.29)'"
as="'int((nf+2)/2) * W/nf * 0.29'" 
ps="'2*int((nf+2)/2) * (W/nf + 0.29)'"
nrd="'0.29 / W'" nrs="'0.29 / W'"
sa=0 sb=0 sd=0
model=pfet_01v8
spiceprefix=X
}
C {sky130_fd_pr/nfet_01v8.sym} 990 -1640 2 1 {name=M17
L=0.15
W=1
nf=1 
mult=1
ad="'int((nf+1)/2) * W/nf * 0.29'" 
pd="'2*int((nf+1)/2) * (W/nf + 0.29)'"
as="'int((nf+2)/2) * W/nf * 0.29'" 
ps="'2*int((nf+2)/2) * (W/nf + 0.29)'"
nrd="'0.29 / W'" nrs="'0.29 / W'"
sa=0 sb=0 sd=0
model=nfet_01v8
spiceprefix=X
}
C {devices/gnd.sym} 1010 -1570 0 0 {name=l20 lab=GND}
C {devices/vdd.sym} 1010 -1810 0 0 {name=l21 lab=VDD}
C {sky130_fd_pr/pfet_01v8.sym} 1980 -1300 0 0 {name=M22
L=0.15
W=2
nf=2
mult=1
ad="'int((nf+1)/2) * W/nf * 0.29'" 
pd="'2*int((nf+1)/2) * (W/nf + 0.29)'"
as="'int((nf+2)/2) * W/nf * 0.29'" 
ps="'2*int((nf+2)/2) * (W/nf + 0.29)'"
nrd="'0.29 / W'" nrs="'0.29 / W'"
sa=0 sb=0 sd=0
model=pfet_01v8
spiceprefix=X
}
C {sky130_fd_pr/nfet_01v8.sym} 1980 -1200 2 1 {name=M23
L=0.15
W=1
nf=1 
mult=1
ad="'int((nf+1)/2) * W/nf * 0.29'" 
pd="'2*int((nf+1)/2) * (W/nf + 0.29)'"
as="'int((nf+2)/2) * W/nf * 0.29'" 
ps="'2*int((nf+2)/2) * (W/nf + 0.29)'"
nrd="'0.29 / W'" nrs="'0.29 / W'"
sa=0 sb=0 sd=0
model=nfet_01v8
spiceprefix=X
}
C {devices/gnd.sym} 2000 -1130 0 0 {name=l22 lab=GND}
C {devices/vdd.sym} 2000 -1370 0 0 {name=l23 lab=VDD}
C {sky130_fd_pr/pfet_01v8.sym} 1980 -1740 0 0 {name=M20
L=0.15
W=2
nf=2
mult=1
ad="'int((nf+1)/2) * W/nf * 0.29'" 
pd="'2*int((nf+1)/2) * (W/nf + 0.29)'"
as="'int((nf+2)/2) * W/nf * 0.29'" 
ps="'2*int((nf+2)/2) * (W/nf + 0.29)'"
nrd="'0.29 / W'" nrs="'0.29 / W'"
sa=0 sb=0 sd=0
model=pfet_01v8
spiceprefix=X
}
C {sky130_fd_pr/nfet_01v8.sym} 1980 -1640 2 1 {name=M21
L=0.15
W=1
nf=1 
mult=1
ad="'int((nf+1)/2) * W/nf * 0.29'" 
pd="'2*int((nf+1)/2) * (W/nf + 0.29)'"
as="'int((nf+2)/2) * W/nf * 0.29'" 
ps="'2*int((nf+2)/2) * (W/nf + 0.29)'"
nrd="'0.29 / W'" nrs="'0.29 / W'"
sa=0 sb=0 sd=0
model=nfet_01v8
spiceprefix=X
}
C {devices/gnd.sym} 2000 -1570 0 0 {name=l24 lab=GND}
C {devices/vdd.sym} 2000 -1810 0 0 {name=l25 lab=VDD}
C {devices/lab_wire.sym} 1170 -1860 0 1 {name=p16 sig_type=std_logic lab=I_IN}
C {devices/ammeter.sym} 1170 -1130 0 0 {name=Vmeas savecurrent=true spice_ignore=0}
C {devices/ammeter.sym} 1440 -1120 0 0 {name=Vmeas1 savecurrent=true spice_ignore=0}
C {devices/lab_wire.sym} 810 -1250 2 0 {name=p10 sig_type=std_logic lab=DOWN_PFD_b}
C {devices/lab_wire.sym} 2150 -1250 0 1 {name=p21 sig_type=std_logic lab=DOWN}
C {devices/ammeter.sym} 2600 -1680 0 0 {name=Vmeas2 savecurrent=true spice_ignore=0}
C {devices/ammeter.sym} 2710 -1430 3 0 {name=Vmeas4 savecurrent=true spice_ignore=0}
C {sky130_fd_pr/nfet_01v8.sym} 2150 -2120 1 0 {name=M8
L=0.15
W=1
nf=1 
mult=1
ad="'int((nf+1)/2) * W/nf * 0.29'" 
pd="'2*int((nf+1)/2) * (W/nf + 0.29)'"
as="'int((nf+2)/2) * W/nf * 0.29'" 
ps="'2*int((nf+2)/2) * (W/nf + 0.29)'"
nrd="'0.29 / W'" nrs="'0.29 / W'"
sa=0 sb=0 sd=0
model=nfet_01v8
spiceprefix=X
}
C {sky130_fd_pr/pfet_01v8.sym} 2150 -840 1 1 {name=M11
L=0.15
W=2
nf=2
mult=1
ad="'int((nf+1)/2) * W/nf * 0.29'" 
pd="'2*int((nf+1)/2) * (W/nf + 0.29)'"
as="'int((nf+2)/2) * W/nf * 0.29'" 
ps="'2*int((nf+2)/2) * (W/nf + 0.29)'"
nrd="'0.29 / W'" nrs="'0.29 / W'"
sa=0 sb=0 sd=0
model=pfet_01v8
spiceprefix=X
}
C {devices/vdd.sym} 2150 -1940 0 0 {name=l5 lab=VDD}
C {devices/gnd.sym} 2150 -2100 0 0 {name=l27 lab=GND}
C {devices/gnd.sym} 2150 -1050 0 0 {name=l28 lab=GND}
C {devices/vdd.sym} 2150 -860 0 0 {name=l29 lab=VDD}
C {sky130_fd_pr/cap_mim_m3_1.sym} 2290 -1770 0 0 {name=C3 model=cap_mim_m3_1 W=6 L=4.2 MF=1 spiceprefix=X}
C {sky130_fd_pr/cap_mim_m3_1.sym} 2290 -1170 0 0 {name=C4 model=cap_mim_m3_1 W=2.6 L=2.6 MF=1 spiceprefix=X}
C {devices/gnd.sym} 1010 -1350 0 0 {name=l30 lab=GND}
C {devices/vdd.sym} 1010 -1160 0 0 {name=l31 lab=VDD}
C {devices/lab_wire.sym} 1360 -950 0 0 {name=p18 sig_type=std_logic lab=DOWN_gate}
C {devices/lab_wire.sym} 3950 -1430 0 1 {name=p1 sig_type=std_logic lab=V_OSC}
C {/foss/designs/my_design/projects/pll/vco/xschem_ngspice/current_starved_VCO10.sym} 3780 -1430 0 0 {name=x1}
C {devices/lab_wire.sym} 4400 -1430 2 0 {name=p24 sig_type=std_logic lab=V_OUT120}
C {/foss/designs/my_design/projects/pll/divider/xschem_ngspice/divide_by_120/divide_by_120_6.sym} 4140 -1430 0 0 {name=x3}
C {devices/gnd.sym} 3780 -1330 0 0 {name=l32 lab=GND}
C {devices/vdd.sym} 3780 -1530 0 0 {name=l33 lab=VDD}
C {devices/gnd.sym} 4140 -1380 0 0 {name=l34 lab=GND}
C {devices/vdd.sym} 4140 -1480 0 0 {name=l35 lab=VDD}
C {/foss/designs/my_design/projects/pll/charge_pump/xschem_ngspice/rail_to_rail_opamp6.sym} 3390 -1410 2 1 {name=x5}
C {devices/vdd.sym} 3390 -1480 0 0 {name=l36 lab=VDD}
C {devices/gnd.sym} 3390 -1340 0 0 {name=l37 lab=GND}
